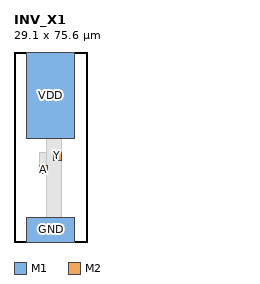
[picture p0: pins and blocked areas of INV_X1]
MACRO INV_X1
  CLASS CORE ;
  ORIGIN 0 0 ;
  SIZE 29.100 BY 75.600 ;
  SYMMETRY X Y ;
  SITE TR1um_access_site ;
  PIN VDD
    DIRECTION INOUT ;
    USE POWER ;
    PORT
      LAYER M1 ;
        RECT 5.000 41.000 24.100 75.600 ;
    END
  END VDD
  PIN GND
    DIRECTION INOUT ;
    USE GROUND ;
    PORT
      LAYER M1 ;
        RECT 5.000 0.000 24.100 9.800 ;
    END
  END GND
  PIN A
    DIRECTION INPUT ;
    USE SIGNAL ;
    PORT
      LAYER M2 ;
        RECT 10.100 27.100 13.500 30.500 ;
    END
  END A
  PIN Y
    DIRECTION OUTPUT ;
    USE SIGNAL ;
    PORT
      LAYER M2 ;
        RECT 15.600 32.600 19.000 36.000 ;
    END
  END Y
  OBS
    LAYER M1 ;
      RECT 10.100 27.100 13.500 35.500 ;
    LAYER M1 ;
      RECT 13.100 6.400 19.000 51.200 ;
    LAYER V1 ;
      RECT 11.100 28.100 12.500 29.500 ;
    LAYER V1 ;
      RECT 16.600 33.600 18.000 35.000 ;
  END
END INV_X1
